# ior7f701503 register map
Registers are 8-bit, access not given, no defined reset value unless marked. A register's access mark holds for its fields unless they carry their own. Addresses are absolute; registers are grouped by the start of their names; [hi:lo] are bit positions; {n}, {i} and the like mark numbered series.

## SFR (part 4 of 4)
0xFFFEEA37 ICCSIH1IREH_1
  [7] CTCSIG0IC ro, [7] CTCSIH1IRE_1 ro, [4] RFCSIG0IC, [4] RFCSIH1IRE_1
0xFFFEEA38 ICCSIG0IR 16-bit
0xFFFEEA38 ICCSIG0IRL
0xFFFEEA38 ICCSIH1IJC_1 16-bit
0xFFFEEA38 ICCSIH1IJCL_1
  [7] MKCSIG0IR, [7] MKCSIH1IJC_1, [6] TBCSIG0IR, [6] TBCSIH1IJC_1, [n] P{n}CSIG0IR (n=0..3), [n] P{n}CSIH1IJC_1 (n=0..3)
0xFFFEEA39 ICCSIG0IRH
0xFFFEEA39 ICCSIH1IJCH_1
  [7] CTCSIG0IR ro, [7] CTCSIH1IJC_1 ro, [4] RFCSIG0IR, [4] RFCSIH1IJC_1
0xFFFEEA3A ICCSIH0IC 16-bit
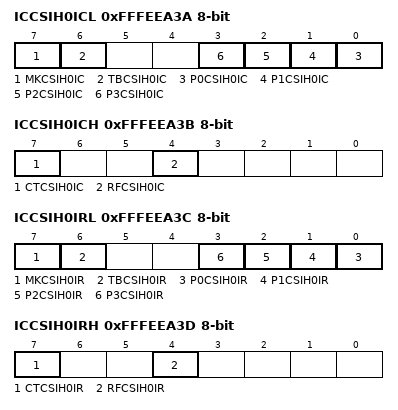
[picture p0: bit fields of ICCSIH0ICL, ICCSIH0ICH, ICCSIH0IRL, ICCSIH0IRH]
0xFFFEEA3A ICCSIH0ICL
  [7] MKCSIH0IC, [6] TBCSIH0IC, [n] P{n}CSIH0IC (n=0..3)
0xFFFEEA3B ICCSIH0ICH
  [7] CTCSIH0IC ro, [4] RFCSIH0IC
0xFFFEEA3C ICCSIH0IR 16-bit
0xFFFEEA3C ICCSIH0IRL
  [7] MKCSIH0IR, [6] TBCSIH0IR, [n] P{n}CSIH0IR (n=0..3)
0xFFFEEA3D ICCSIH0IRH
  [7] CTCSIH0IR ro, [4] RFCSIH0IR
0xFFFEEA3E ICCSIH0IRE 16-bit
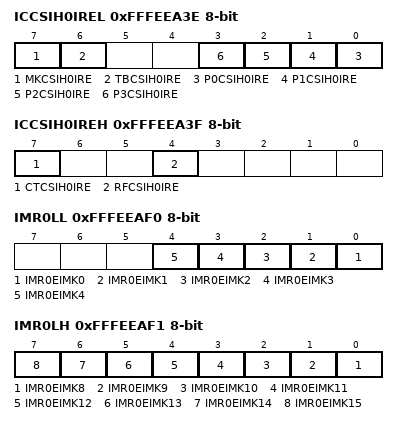
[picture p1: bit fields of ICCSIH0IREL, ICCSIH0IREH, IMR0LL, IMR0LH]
0xFFFEEA3E ICCSIH0IREL
  [7] MKCSIH0IRE, [6] TBCSIH0IRE, [n] P{n}CSIH0IRE (n=0..3)
0xFFFEEA3F ICCSIH0IREH
  [7] CTCSIH0IRE ro, [4] RFCSIH0IRE
0xFFFEEA78 FNC 16-bit ro
0xFFFEEA79 FNCH ro
  [4] FNRF
0xFFFEEA7A FIC 16-bit ro
0xFFFEEA7B FICH ro
  [4] FIRF
0xFFFEEAF0 IMR0 32-bit
0xFFFEEAF0 IMR0L 16-bit
0xFFFEEAF0 IMR0LL
  [n] IMR0EIMK{n} (n=0..4)
0xFFFEEAF1 IMR0LH
  [n-8] IMR0EIMK{n} (n=8..15)
0xFFFEEAF2 IMR0H 16-bit
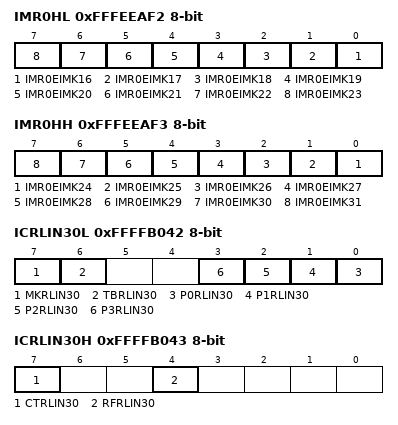
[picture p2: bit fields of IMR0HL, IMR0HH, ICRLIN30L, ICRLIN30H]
0xFFFEEAF2 IMR0HL
  [n-16] IMR0EIMK{n} (n=16..23)
0xFFFEEAF3 IMR0HH
  [n-24] IMR0EIMK{n} (n=24..31)
{0xFFFEEB00+4i} IBDIPIR{i} 32-bit (i=0..3)
0xFFFEEB10 IBDBN0 32-bit
0xFFFEEB20 IBDTAUD0I0 32-bit
0xFFFEEB20 IBDCSIH2IC_1 32-bit
0xFFFEEB24 IBDTAUD0I2 32-bit
0xFFFEEB24 IBDCSIH3IC_1 32-bit
0xFFFEEB28 IBDTAUD0I4 32-bit
0xFFFEEB28 IBDCSIH2IR_1 32-bit
0xFFFEEB2C IBDTAUD0I6 32-bit
0xFFFEEB2C IBDCSIH2IRE_1 32-bit
0xFFFEEB30 IBDTAUD0I8 32-bit
0xFFFEEB30 IBDCSIH2IJC_1 32-bit
0xFFFEEB34 IBDTAUD0I10 32-bit
0xFFFEEB34 IBDCSIH3IR_1 32-bit
0xFFFEEB38 IBDTAUD0I12 32-bit
0xFFFEEB38 IBDCSIH3IRE_1 32-bit
0xFFFEEB3C IBDTAUD0I14 32-bit
0xFFFEEB3C IBDCSIH3IJC_1 32-bit
0xFFFEEB40 IBDTAPA0IPEK0 32-bit
0xFFFEEB40 IBDCSIH1IC_1 32-bit
0xFFFEEB44 IBDTAPA0IVLY0 32-bit
0xFFFEEB44 IBDCSIH1IR_1 32-bit
{0xFFFEEB48+4i} IBDADCA0I{i} 32-bit (i=0..2)
0xFFFEEB50 IBDCSIH0IJC_1 32-bit
0xFFFEEB54 IBDDCUTDI 32-bit
0xFFFEEB58 IBDRCANGERR0 32-bit
0xFFFEEB5C IBDRCANGRECC0 32-bit
0xFFFEEB60 IBDRCAN0ERR 32-bit
0xFFFEEB64 IBDRCAN0REC 32-bit
0xFFFEEB68 IBDRCAN0TRX 32-bit
0xFFFEEB6C IBDCSIG0IC 32-bit
0xFFFEEB6C IBDCSIH1IRE_1 32-bit
0xFFFEEB70 IBDCSIG0IR 32-bit
0xFFFEEB70 IBDCSIH1IJC_1 32-bit
0xFFFEEB74 IBDCSIH0IC 32-bit
0xFFFEEB78 IBDCSIH0IR 32-bit
0xFFFEEB7C IBDCSIH0IRE 32-bit
{0xFFFEEC00+4i} G0MEV{i} 32-bit (i=0..31)
{0xFFFEEC00+4i} G0MEV{i}L 16-bit (i=0..31)
{0xFFFEEC00+4i} G0MEV{i}LL (i=0..31)
{0xFFFEEC01+4i} G0MEV{i}LH (i=0..31)
{0xFFFEEC02+4i} G0MEV{i}H 16-bit (i=0..31)
{0xFFFEEC02+4i} G0MEV{i}HL (i=0..31)
{0xFFFEEC03+4i} G0MEV{i}HH (i=0..31)
0xFFFF8000 DMACTL 32-bit
0xFFFF8020 DMACER 32-bit ro
0xFFFF8030 DM0CMV 32-bit ro
0xFFFF8034 DM1CMV 32-bit ro
0xFFFF803C CMVC 32-bit
0xFFFF8040 DM2CMV 32-bit ro
0xFFFF8044 DM3CMV 32-bit ro
{0xFFFF8100+4i} DM{i:02}CM 32-bit (i=0..7)
{0xFFFF80F8+4i} DM{i}CM 32-bit (i=10..17)
{0xFFFF80F0+4i} DM{i}CM 32-bit (i=20..27)
{0xFFFF80E8+4i} DM{i}CM 32-bit (i=30..37)
{0xFFFF8400+0x40*i} DSA{i} 32-bit (i=0..31)
{0xFFFF8404+0x40*i} DDA{i} 32-bit (i=0..31)
{0xFFFF8408+0x40*i} DTC{i} 32-bit (i=0..31)
{0xFFFF840C+0x40*i} DTCT{i} 32-bit (i=0..31)
{0xFFFF8410+0x40*i} DRSA{i} 32-bit (i=0..31)
{0xFFFF8414+0x40*i} DRDA{i} 32-bit (i=0..31)
{0xFFFF8418+0x40*i} DRTC{i} 32-bit (i=0..31)
{0xFFFF841C+0x40*i} DTCC{i} 32-bit (i=0..31)
{0xFFFF8420+0x40*i} DCEN{i} 32-bit (i=0..31)
{0xFFFF8424+0x40*i} DCST{i} 32-bit ro (i=0..31)
{0xFFFF8428+0x40*i} DCSTS{i} 32-bit (i=0..31)
{0xFFFF842C+0x40*i} DCSTC{i} 32-bit (i=0..31)
{0xFFFF8430+0x40*i} DTFR{i} 32-bit (i=0..31)
{0xFFFF8434+0x40*i} DTFRRQ{i} 32-bit ro (i=0..31)
{0xFFFF8438+0x40*i} DTFRRQC{i} 32-bit (i=0..31)
0xFFFFB040 ICCSIH0IJC 16-bit
0xFFFFB040 ICCSIH0IJCL
  [7] MKADCA0I2_2, [7] MKCSIH0IJC, [6] TBADCA0I2_2, [6] TBCSIH0IJC, [n] P{n}ADCA0I2_2 (n=0..3), [n] P{n}CSIH0IJC (n=0..3)
0xFFFFB040 ICADCA0I2_2 16-bit
0xFFFFB040 ICADCA0I2L_2
0xFFFFB041 ICCSIH0IJCH
  [7] CTADCA0I2_2 ro, [7] CTCSIH0IJC ro, [4] RFADCA0I2_2, [4] RFCSIH0IJC
0xFFFFB041 ICADCA0I2H_2
0xFFFFB042 ICRLIN30 16-bit
0xFFFFB042 ICRLIN30L
  [7] MKRLIN30, [6] TBRLIN30, [n] P{n}RLIN30 (n=0..3)
0xFFFFB043 ICRLIN30H
  [7] CTRLIN30 ro, [4] RFRLIN30
{0xFFFFB044+2i} ICRLIN30UR{i} 16-bit (i=0..2)
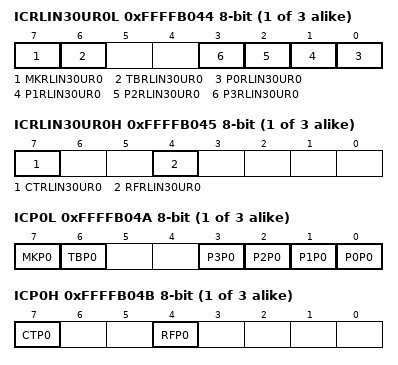
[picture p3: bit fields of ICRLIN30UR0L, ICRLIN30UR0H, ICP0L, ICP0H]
{0xFFFFB044+2i} ICRLIN30UR{i}L (i=0..2)
  [7] MKRLIN30UR{i}, [6] TBRLIN30UR{i}, [n] P{n}RLIN30UR{i} (n=0..3)
{0xFFFFB045+2i} ICRLIN30UR{i}H (i=0..2)
  [7] CTRLIN30UR{i} ro, [4] RFRLIN30UR{i}
{0xFFFFB04A+2i} ICP{i} 16-bit (i=0..2)
{0xFFFFB04A+2i} ICP{i}L (i=0..2)
  [7] MKP{i}, [6] TBP{i}, [n] P{n}P{i} (n=0..3)
{0xFFFFB04B+2i} ICP{i}H (i=0..2)
  [7] CTP{i} ro, [4] RFP{i}
{0xFFFFB050+2i} ICWDTA{i} 16-bit (i=0..2)
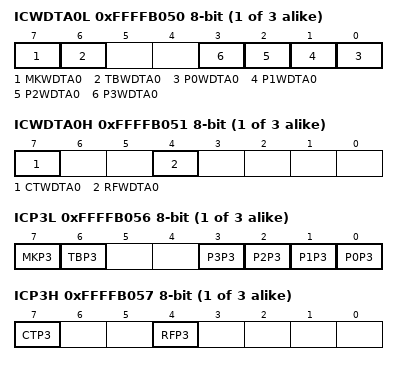
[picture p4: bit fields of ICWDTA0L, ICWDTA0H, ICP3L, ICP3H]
{0xFFFFB050+2i} ICWDTA{i}L (i=0..2)
  [7] MKWDTA{i}, [6] TBWDTA{i}, [n] P{n}WDTA{i} (n=0..3)
{0xFFFFB051+2i} ICWDTA{i}H (i=0..2)
  [7] CTWDTA{i} ro, [4] RFWDTA{i}
{0xFFFFB050+2i} ICP{i} 16-bit (i=3..5)
{0xFFFFB050+2i} ICP{i}L (i=3..5)
  [7] MKP{i}, [6] TBP{i}, [n] P{n}P{i} (n=0..3)
{0xFFFFB051+2i} ICP{i}H (i=3..5)
  [7] CTP{i} ro, [4] RFP{i}
0xFFFFB05C ICP10 16-bit
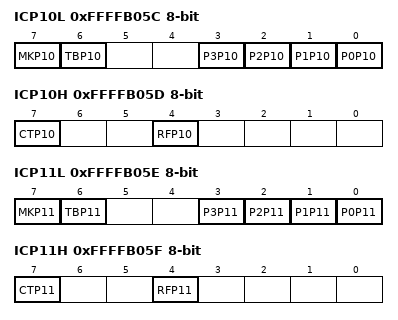
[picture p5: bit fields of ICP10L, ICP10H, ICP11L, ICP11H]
0xFFFFB05C ICP10L
  [7] MKP10, [6] TBP10, [n] P{n}P10 (n=0..3)
0xFFFFB05D ICP10H
  [7] CTP10 ro, [4] RFP10
0xFFFFB05E ICP11 16-bit
0xFFFFB05E ICP11L
  [7] MKP11, [6] TBP11, [n] P{n}P11 (n=0..3)
0xFFFFB05F ICP11H
  [7] CTP11 ro, [4] RFP11
0xFFFFB060 ICTAUD0I1 16-bit
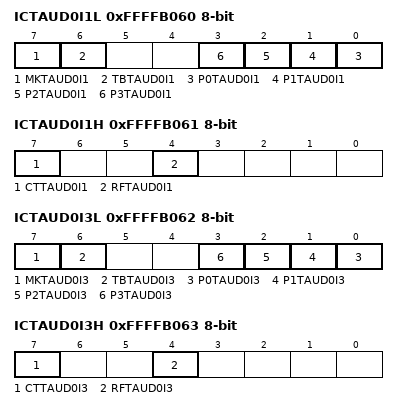
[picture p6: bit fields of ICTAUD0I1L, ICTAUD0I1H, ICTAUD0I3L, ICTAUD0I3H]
0xFFFFB060 ICTAUD0I1L
  [7] MKTAUD0I1, [6] TBTAUD0I1, [n] P{n}TAUD0I1 (n=0..3)
0xFFFFB061 ICTAUD0I1H
  [7] CTTAUD0I1 ro, [4] RFTAUD0I1
0xFFFFB062 ICTAUD0I3 16-bit
0xFFFFB062 ICTAUD0I3L
  [7] MKTAUD0I3, [6] TBTAUD0I3, [n] P{n}TAUD0I3 (n=0..3)
0xFFFFB063 ICTAUD0I3H
  [7] CTTAUD0I3 ro, [4] RFTAUD0I3
0xFFFFB064 ICTAUD0I5 16-bit
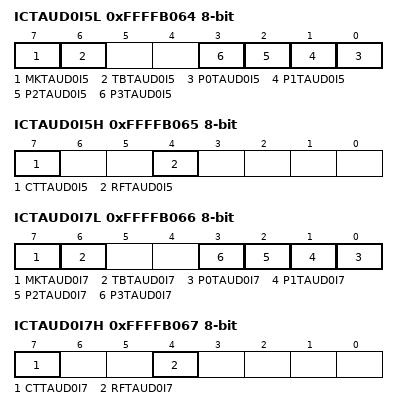
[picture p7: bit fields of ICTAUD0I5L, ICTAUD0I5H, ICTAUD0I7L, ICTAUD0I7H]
0xFFFFB064 ICTAUD0I5L
  [7] MKTAUD0I5, [6] TBTAUD0I5, [n] P{n}TAUD0I5 (n=0..3)
0xFFFFB065 ICTAUD0I5H
  [7] CTTAUD0I5 ro, [4] RFTAUD0I5
0xFFFFB066 ICTAUD0I7 16-bit
0xFFFFB066 ICTAUD0I7L
  [7] MKTAUD0I7, [6] TBTAUD0I7, [n] P{n}TAUD0I7 (n=0..3)
0xFFFFB067 ICTAUD0I7H
  [7] CTTAUD0I7 ro, [4] RFTAUD0I7
0xFFFFB068 ICTAUD0I9 16-bit
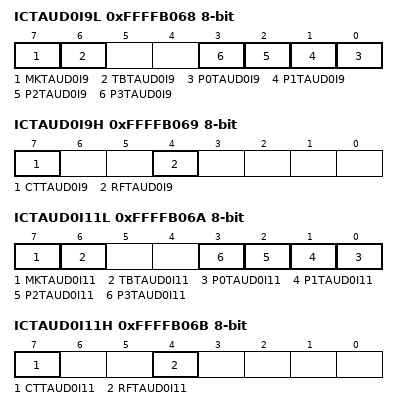
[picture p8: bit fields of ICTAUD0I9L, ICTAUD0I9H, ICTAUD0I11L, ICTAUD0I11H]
0xFFFFB068 ICTAUD0I9L
  [7] MKTAUD0I9, [6] TBTAUD0I9, [n] P{n}TAUD0I9 (n=0..3)
0xFFFFB069 ICTAUD0I9H
  [7] CTTAUD0I9 ro, [4] RFTAUD0I9
0xFFFFB06A ICTAUD0I11 16-bit
0xFFFFB06A ICTAUD0I11L
  [7] MKTAUD0I11, [6] TBTAUD0I11, [n] P{n}TAUD0I11 (n=0..3)
0xFFFFB06B ICTAUD0I11H
  [7] CTTAUD0I11 ro, [4] RFTAUD0I11
0xFFFFB06C ICTAUD0I13 16-bit
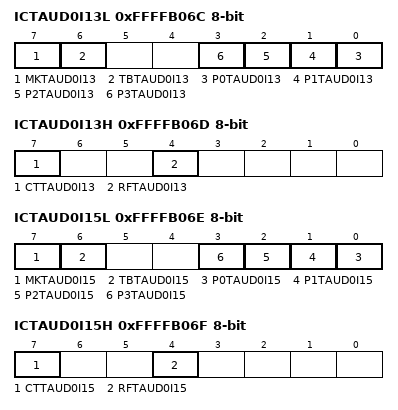
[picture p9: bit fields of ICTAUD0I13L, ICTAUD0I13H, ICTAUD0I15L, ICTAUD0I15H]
0xFFFFB06C ICTAUD0I13L
  [7] MKTAUD0I13, [6] TBTAUD0I13, [n] P{n}TAUD0I13 (n=0..3)
0xFFFFB06D ICTAUD0I13H
  [7] CTTAUD0I13 ro, [4] RFTAUD0I13
0xFFFFB06E ICTAUD0I15 16-bit
0xFFFFB06E ICTAUD0I15L
  [7] MKTAUD0I15, [6] TBTAUD0I15, [n] P{n}TAUD0I15 (n=0..3)
0xFFFFB06F ICTAUD0I15H
  [7] CTTAUD0I15 ro, [4] RFTAUD0I15
0xFFFFB070 ICADCA0ERR 16-bit
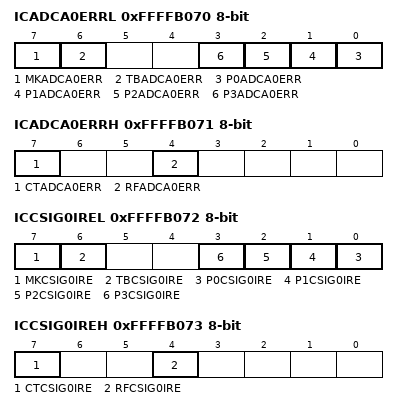
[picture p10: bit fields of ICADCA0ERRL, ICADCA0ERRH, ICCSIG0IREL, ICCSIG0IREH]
0xFFFFB070 ICADCA0ERRL
  [7] MKADCA0ERR, [6] TBADCA0ERR, [n] P{n}ADCA0ERR (n=0..3)
0xFFFFB071 ICADCA0ERRH
  [7] CTADCA0ERR ro, [4] RFADCA0ERR
0xFFFFB072 ICCSIG0IRE 16-bit
0xFFFFB072 ICCSIG0IREL
  [7] MKCSIG0IRE, [6] TBCSIG0IRE, [n] P{n}CSIG0IRE (n=0..3)
0xFFFFB073 ICCSIG0IREH
  [7] CTCSIG0IRE ro, [4] RFCSIG0IRE
0xFFFFB074 ICRLIN20 16-bit
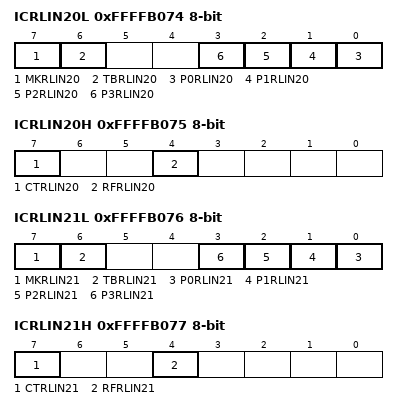
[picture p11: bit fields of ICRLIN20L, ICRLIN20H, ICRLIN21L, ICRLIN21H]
0xFFFFB074 ICRLIN20L
  [7] MKRLIN20, [6] TBRLIN20, [n] P{n}RLIN20 (n=0..3)
0xFFFFB075 ICRLIN20H
  [7] CTRLIN20 ro, [4] RFRLIN20
0xFFFFB076 ICRLIN21 16-bit
0xFFFFB076 ICRLIN21L
  [7] MKRLIN21, [6] TBRLIN21, [n] P{n}RLIN21 (n=0..3)
0xFFFFB077 ICRLIN21H
  [7] CTRLIN21 ro, [4] RFRLIN21
{0xFFFFB078+2i} ICDMA{i} 16-bit (i=0..15)
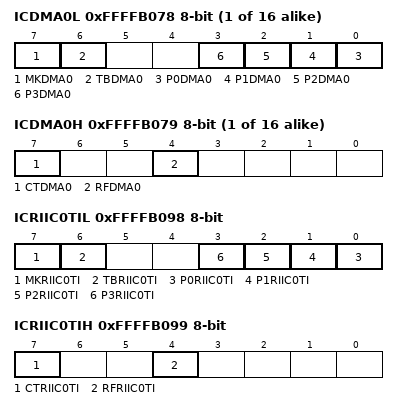
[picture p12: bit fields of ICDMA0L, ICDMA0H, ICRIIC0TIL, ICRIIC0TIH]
{0xFFFFB078+2i} ICDMA{i}L (i=0..15)
  [7] MKDMA{i}, [6] TBDMA{i}, [n] P{n}DMA{i} (n=0..3)
{0xFFFFB079+2i} ICDMA{i}H (i=0..15)
  [7] CTDMA{i} ro, [4] RFDMA{i}
0xFFFFB098 ICRIIC0TI 16-bit
0xFFFFB098 ICRIIC0TIL
  [7] MKRIIC0TI, [6] TBRIIC0TI, [n] P{n}RIIC0TI (n=0..3)
0xFFFFB099 ICRIIC0TIH
  [7] CTRIIC0TI ro, [4] RFRIIC0TI
0xFFFFB09A ICRIIC0TEI 16-bit
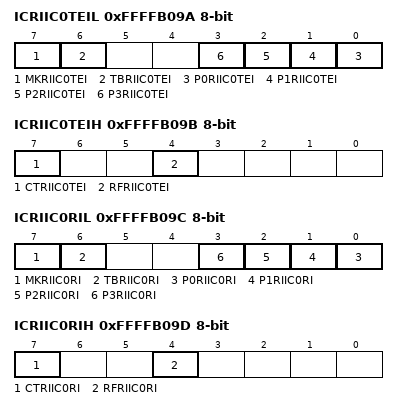
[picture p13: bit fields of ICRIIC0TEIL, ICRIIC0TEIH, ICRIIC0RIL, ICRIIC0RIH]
0xFFFFB09A ICRIIC0TEIL
  [7] MKRIIC0TEI, [6] TBRIIC0TEI, [n] P{n}RIIC0TEI (n=0..3)
0xFFFFB09B ICRIIC0TEIH
  [7] CTRIIC0TEI ro, [4] RFRIIC0TEI
0xFFFFB09C ICRIIC0RI 16-bit
0xFFFFB09C ICRIIC0RIL
  [7] MKRIIC0RI, [6] TBRIIC0RI, [n] P{n}RIIC0RI (n=0..3)
0xFFFFB09D ICRIIC0RIH
  [7] CTRIIC0RI ro, [4] RFRIIC0RI
0xFFFFB09E ICRIIC0EE 16-bit
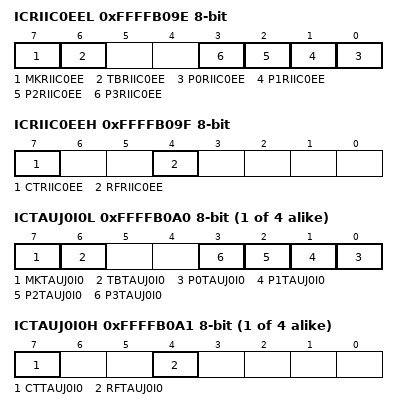
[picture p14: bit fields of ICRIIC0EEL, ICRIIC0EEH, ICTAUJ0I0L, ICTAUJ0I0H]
0xFFFFB09E ICRIIC0EEL
  [7] MKRIIC0EE, [6] TBRIIC0EE, [n] P{n}RIIC0EE (n=0..3)
0xFFFFB09F ICRIIC0EEH
  [7] CTRIIC0EE ro, [4] RFRIIC0EE
{0xFFFFB0A0+2i} ICTAUJ0I{i} 16-bit (i=0..3)
{0xFFFFB0A0+2i} ICTAUJ0I{i}L (i=0..3)
  [7] MKTAUJ0I{i}, [6] TBTAUJ0I{i}, [n] P{n}TAUJ0I{i} (n=0..3)
{0xFFFFB0A1+2i} ICTAUJ0I{i}H (i=0..3)
  [7] CTTAUJ0I{i} ro, [4] RFTAUJ0I{i}
0xFFFFB0A8 ICOSTM0 16-bit
0xFFFFB0A8 ICOSTM0L
  [7] MKOSTM0, [6] TBOSTM0, [n] P{n}OSTM0 (n=0..3)
0xFFFFB0A9 ICOSTM0H
  [7] CTOSTM0 ro, [4] RFOSTM0
0xFFFFB0AA ICENCA0IOV 16-bit
{0xFFFFB0A2+2i} ICPWGA{i} 16-bit (i=4..7)
0xFFFFB0AA ICENCA0IOVL
0xFFFFB0AA ICPWGA4L
  [7] MKENCA0IOV, [7] MKPWGA4, [6] TBENCA0IOV, [6] TBPWGA4, [n] P{n}ENCA0IOV (n=0..3), [n] P{n}PWGA4 (n=0..3)
0xFFFFB0AB ICENCA0IOVH
0xFFFFB0AB ICPWGA4H
  [7] CTENCA0IOV ro, [7] CTPWGA4 ro, [4] RFENCA0IOV, [4] RFPWGA4
0xFFFFB0AC ICENCA0IUD 16-bit
0xFFFFB0AC ICENCA0IUDL
0xFFFFB0AC ICPWGA5L
  [7] MKENCA0IUD, [7] MKPWGA5, [6] TBENCA0IUD, [6] TBPWGA5, [n] P{n}ENCA0IUD (n=0..3), [n] P{n}PWGA5 (n=0..3)
0xFFFFB0AD ICENCA0IUDH
0xFFFFB0AD ICPWGA5H
  [7] CTENCA0IUD ro, [7] CTPWGA5 ro, [4] RFENCA0IUD, [4] RFPWGA5
0xFFFFB0AE ICENCA0I0 16-bit
0xFFFFB0AE ICENCA0I0L
0xFFFFB0AE ICPWGA6L
  [7] MKENCA0I0, [7] MKPWGA6, [6] TBENCA0I0, [6] TBPWGA6, [n] P{n}ENCA0I0 (n=0..3), [n] P{n}PWGA6 (n=0..3)
0xFFFFB0AF ICENCA0I0H
0xFFFFB0AF ICPWGA6H
  [7] CTENCA0I0 ro, [7] CTPWGA6 ro, [4] RFENCA0I0, [4] RFPWGA6
0xFFFFB0B0 ICENCA0I1 16-bit
0xFFFFB0B0 ICENCA0I1L
0xFFFFB0B0 ICPWGA7L
  [7] MKENCA0I1, [7] MKPWGA7, [6] TBENCA0I1, [6] TBPWGA7, [n] P{n}ENCA0I1 (n=0..3), [n] P{n}PWGA7 (n=0..3)
0xFFFFB0B1 ICENCA0I1H
0xFFFFB0B1 ICPWGA7H
  [7] CTENCA0I1 ro, [7] CTPWGA7 ro, [4] RFENCA0I1, [4] RFPWGA7
0xFFFFB0B2 ICENCA0IEC 16-bit
0xFFFFB0B2 ICENCA0IECL
  [7] MKENCA0IEC, [6] TBENCA0IEC, [n] P{n}ENCA0IEC (n=0..3)
0xFFFFB0B3 ICENCA0IECH
  [7] CTENCA0IEC ro, [4] RFENCA0IEC
0xFFFFB0B4 ICKR0 16-bit
0xFFFFB0B4 ICKR0L
  [7] MKKR0, [6] TBKR0, [n] P{n}KR0 (n=0..3)
0xFFFFB0B5 ICKR0H
  [7] CTKR0 ro, [4] RFKR0
0xFFFFB0B6 ICQFULL 16-bit
0xFFFFB0B6 ICQFULLL
  [7] MKQFULL, [6] TBQFULL, [n] P{n}QFULL (n=0..3)
0xFFFFB0B7 ICQFULLH
  [7] CTQFULL ro, [4] RFQFULL
{0xFFFFB0B8+2i} ICPWGA{i} 16-bit (i=0..3)
{0xFFFFB0B8+2i} ICPWGA{i}L (i=0..3)
  [7] MKPWGA{i}, [6] TBPWGA{i}, [n] P{n}PWGA{i} (n=0..3)
{0xFFFFB0B9+2i} ICPWGA{i}H (i=0..3)
  [7] CTPWGA{i} ro, [4] RFPWGA{i}
{0xFFFFB0B0+2i} ICPWGA{i} 16-bit (i=8..15)
{0xFFFFB0B0+2i} ICPWGA{i}L (i=8..15)
  [7] MKPWGA{i}, [6] TBPWGA{i}, [n] P{n}PWGA{i} (n=0..3)
{0xFFFFB0B1+2i} ICPWGA{i}H (i=8..15)
  [7] CTPWGA{i} ro, [4] RFPWGA{i}
0xFFFFB0DC ICFLERR 16-bit
0xFFFFB0DC ICFLERRL
  [7] MKFLERR, [6] TBFLERR, [n] P{n}FLERR (n=0..3)
0xFFFFB0DD ICFLERRH
  [7] CTFLERR ro, [4] RFFLERR
0xFFFFB0DE ICFLENDNM 16-bit
0xFFFFB0DE ICFLENDNML
  [7] MKFLENDNM, [6] TBFLENDNM, [n] P{n}FLENDNM (n=0..3)
0xFFFFB0DF ICFLENDNMH
  [7] CTFLENDNM ro, [4] RFFLENDNM
0xFFFFB0E0 ICCWEND 16-bit
0xFFFFB0E0 ICCWENDL
  [7] MKCWEND, [6] TBCWEND, [n] P{n}CWEND (n=0..3)
0xFFFFB0E1 ICCWENDH
  [7] CTCWEND ro, [4] RFCWEND
0xFFFFB0E2 ICRCAN1ERR 16-bit
0xFFFFB0E2 ICRCAN1ERRL
  [7] MKRCAN1ERR, [6] TBRCAN1ERR, [n] P{n}RCAN1ERR (n=0..3)
0xFFFFB0E3 ICRCAN1ERRH
  [7] CTRCAN1ERR ro, [4] RFRCAN1ERR
0xFFFFB0E4 ICRCAN1REC 16-bit
0xFFFFB0E4 ICRCAN1RECL
  [7] MKRCAN1REC, [6] TBRCAN1REC, [n] P{n}RCAN1REC (n=0..3)
0xFFFFB0E5 ICRCAN1RECH
  [7] CTRCAN1REC ro, [4] RFRCAN1REC
0xFFFFB0E6 ICRCAN1TRX 16-bit
0xFFFFB0E6 ICRCAN1TRXL
  [7] MKRCAN1TRX, [6] TBRCAN1TRX, [n] P{n}RCAN1TRX (n=0..3)
0xFFFFB0E7 ICRCAN1TRXH
  [7] CTRCAN1TRX ro, [4] RFRCAN1TRX
0xFFFFB0E8 ICCSIH1IC 16-bit
0xFFFFB0E8 ICCSIH1ICL
0xFFFFB0E8 ICTAPA0IPEK0_2 16-bit
0xFFFFB0E8 ICTAPA0IPEK0L_2
  [7] MKCSIH1IC, [7] MKTAPA0IPEK0_2, [6] TBCSIH1IC, [6] TBTAPA0IPEK0_2, [n] P{n}CSIH1IC (n=0..3), [n] P{n}TAPA0IPEK0_2 (n=0..3)
0xFFFFB0E9 ICCSIH1ICH
0xFFFFB0E9 ICTAPA0IPEK0H_2
  [7] CTCSIH1IC ro, [7] CTTAPA0IPEK0_2 ro, [4] RFCSIH1IC, [4] RFTAPA0IPEK0_2
0xFFFFB0EA ICCSIH1IR 16-bit
0xFFFFB0EA ICCSIH1IRL
0xFFFFB0EA ICTAPA0IVLY0_2 16-bit
0xFFFFB0EA ICTAPA0IVLY0L_2
  [7] MKCSIH1IR, [7] MKTAPA0IVLY0_2, [6] TBCSIH1IR, [6] TBTAPA0IVLY0_2, [n] P{n}CSIH1IR (n=0..3), [n] P{n}TAPA0IVLY0_2 (n=0..3)
0xFFFFB0EB ICCSIH1IRH
0xFFFFB0EB ICTAPA0IVLY0H_2
  [7] CTCSIH1IR ro, [7] CTTAPA0IVLY0_2 ro, [4] RFCSIH1IR, [4] RFTAPA0IVLY0_2
0xFFFFB0EC ICCSIH1IRE 16-bit
0xFFFFB0EC ICCSIH1IREL
  [7] MKCSIG0IC_2, [7] MKCSIH1IRE, [6] TBCSIG0IC_2, [6] TBCSIH1IRE, [n] P{n}CSIG0IC_2 (n=0..3), [n] P{n}CSIH1IRE (n=0..3)
0xFFFFB0EC ICCSIG0IC_2 16-bit
0xFFFFB0EC ICCSIG0ICL_2
0xFFFFB0ED ICCSIH1IREH
  [7] CTCSIG0IC_2 ro, [7] CTCSIH1IRE ro, [4] RFCSIG0IC_2, [4] RFCSIH1IRE
0xFFFFB0ED ICCSIG0ICH_2
0xFFFFB0EE ICCSIH1IJC 16-bit
0xFFFFB0EE ICCSIH1IJCL
  [7] MKCSIG0IR_2, [7] MKCSIH1IJC, [6] TBCSIG0IR_2, [6] TBCSIH1IJC, [n] P{n}CSIG0IR_2 (n=0..3), [n] P{n}CSIH1IJC (n=0..3)
0xFFFFB0EE ICCSIG0IR_2 16-bit
0xFFFFB0EE ICCSIG0IRL_2
0xFFFFB0EF ICCSIH1IJCH
  [7] CTCSIG0IR_2 ro, [7] CTCSIH1IJC ro, [4] RFCSIG0IR_2, [4] RFCSIH1IJC
0xFFFFB0EF ICCSIG0IRH_2
0xFFFFB0F0 ICRLIN31 16-bit
0xFFFFB0F0 ICRLIN31L
  [7] MKRLIN31, [6] TBRLIN31, [n] P{n}RLIN31 (n=0..3)
0xFFFFB0F1 ICRLIN31H
  [7] CTRLIN31 ro, [4] RFRLIN31
{0xFFFFB0F2+2i} ICRLIN31UR{i} 16-bit (i=0..2)
{0xFFFFB0F2+2i} ICRLIN31UR{i}L (i=0..2)
  [7] MKRLIN31UR{i}, [6] TBRLIN31UR{i}, [n] P{n}RLIN31UR{i} (n=0..3)
{0xFFFFB0F3+2i} ICRLIN31UR{i}H (i=0..2)
  [7] CTRLIN31UR{i} ro, [4] RFRLIN31UR{i}
{0xFFFFB0D0+2i} ICPWGA{i} 16-bit (i=20..23)
{0xFFFFB0D0+2i} ICPWGA{i}L (i=20..23)
  [7] MKPWGA{i}, [6] TBPWGA{i}, [n] P{n}PWGA{i} (n=0..3)
{0xFFFFB0D1+2i} ICPWGA{i}H (i=20..23)
  [7] CTPWGA{i} ro, [4] RFPWGA{i}
{0xFFFFB0F4+2i} ICP{i} 16-bit (i=6..8)
{0xFFFFB0F4+2i} ICP{i}L (i=6..8)
  [7] MKP{i}, [6] TBP{i}, [n] P{n}P{i} (n=0..3)
{0xFFFFB0F5+2i} ICP{i}H (i=6..8)
  [7] CTP{i} ro, [4] RFP{i}
0xFFFFB106 ICP12 16-bit
0xFFFFB106 ICP12L
  [7] MKP12, [6] TBP12, [n] P{n}P12 (n=0..3)
0xFFFFB107 ICP12H
  [7] CTP12 ro, [4] RFP12
0xFFFFB108 ICCSIH2IC 16-bit
0xFFFFB108 ICCSIH2ICL
0xFFFFB108 ICTAUD0I0_2 16-bit
0xFFFFB108 ICTAUD0I0L_2
  [7] MKCSIH2IC, [7] MKTAUD0I0_2, [6] TBCSIH2IC, [6] TBTAUD0I0_2, [n] P{n}CSIH2IC (n=0..3), [n] P{n}TAUD0I0_2 (n=0..3)
0xFFFFB109 ICCSIH2ICH
0xFFFFB109 ICTAUD0I0H_2
  [7] CTCSIH2IC ro, [7] CTTAUD0I0_2 ro, [4] RFCSIH2IC, [4] RFTAUD0I0_2
0xFFFFB10A ICCSIH2IR 16-bit
0xFFFFB10A ICCSIH2IRL
0xFFFFB10A ICTAUD0I4_2 16-bit
0xFFFFB10A ICTAUD0I4L_2
  [7] MKCSIH2IR, [7] MKTAUD0I4_2, [6] TBCSIH2IR, [6] TBTAUD0I4_2, [n] P{n}CSIH2IR (n=0..3), [n] P{n}TAUD0I4_2 (n=0..3)
0xFFFFB10B ICCSIH2IRH
0xFFFFB10B ICTAUD0I4H_2
  [7] CTCSIH2IR ro, [7] CTTAUD0I4_2 ro, [4] RFCSIH2IR, [4] RFTAUD0I4_2
0xFFFFB10C ICCSIH2IRE 16-bit
0xFFFFB10C ICCSIH2IREL
0xFFFFB10C ICTAUD0I6_2 16-bit
0xFFFFB10C ICTAUD0I6L_2
  [7] MKCSIH2IRE, [7] MKTAUD0I6_2, [6] TBCSIH2IRE, [6] TBTAUD0I6_2, [n] P{n}CSIH2IRE (n=0..3), [n] P{n}TAUD0I6_2 (n=0..3)
0xFFFFB10D ICCSIH2IREH
0xFFFFB10D ICTAUD0I6H_2
  [7] CTCSIH2IRE ro, [7] CTTAUD0I6_2 ro, [4] RFCSIH2IRE, [4] RFTAUD0I6_2
0xFFFFB10E ICCSIH2IJC 16-bit
0xFFFFB10E ICCSIH2IJCL
0xFFFFB10E ICTAUD0I8_2 16-bit
0xFFFFB10E ICTAUD0I8L_2
  [7] MKCSIH2IJC, [7] MKTAUD0I8_2, [6] TBCSIH2IJC, [6] TBTAUD0I8_2, [n] P{n}CSIH2IJC (n=0..3), [n] P{n}TAUD0I8_2 (n=0..3)
0xFFFFB10F ICCSIH2IJCH
0xFFFFB10F ICTAUD0I8H_2
  [7] CTCSIH2IJC ro, [7] CTTAUD0I8_2 ro, [4] RFCSIH2IJC, [4] RFTAUD0I8_2
{0xFFFFB11C+2i} ICTAUB0I{i} 16-bit (i=0..15)
{0xFFFFB11C+2i} ICTAUB0I{i}L (i=0..2)
  [7] MKTAUB0I{i}, [6] TBTAUB0I{i}, [n] P{n}TAUB0I{i} (n=0..3)
{0xFFFFB11D+2i} ICTAUB0I{i}H (i=0..2)
  [7] CTTAUB0I{i} ro, [4] RFTAUB0I{i}
{0xFFFFB0E2+4i} ICPWGA{i} 16-bit (i=16..19)
{0xFFFFB0E2+4i} ICPWGA{i}L (i=16..19)
0xFFFFB122 ICTAUB0I3L
  [7] MKPWGA16, [7] MKTAUB0I3, [6] TBPWGA16, [6] TBTAUB0I3, [n] P{n}PWGA16 (n=0..3), [n] P{n}TAUB0I3 (n=0..3)
{0xFFFFB0E3+4i} ICPWGA{i}H (i=16..19)
0xFFFFB123 ICTAUB0I3H
  [7] CTPWGA16 ro, [7] CTTAUB0I3 ro, [4] RFPWGA16, [4] RFTAUB0I3
0xFFFFB124 ICTAUB0I4L
  [7] MKTAUB0I4, [6] TBTAUB0I4, [n] P{n}TAUB0I4 (n=0..3)
0xFFFFB125 ICTAUB0I4H
  [7] CTTAUB0I4 ro, [4] RFTAUB0I4
0xFFFFB126 ICTAUB0I5L
  [7] MKPWGA17, [7] MKTAUB0I5, [6] TBPWGA17, [6] TBTAUB0I5, [n] P{n}PWGA17 (n=0..3), [n] P{n}TAUB0I5 (n=0..3)
0xFFFFB127 ICTAUB0I5H
  [7] CTPWGA17 ro, [7] CTTAUB0I5 ro, [4] RFPWGA17, [4] RFTAUB0I5
0xFFFFB128 ICTAUB0I6L
  [7] MKTAUB0I6, [6] TBTAUB0I6, [n] P{n}TAUB0I6 (n=0..3)
0xFFFFB129 ICTAUB0I6H
  [7] CTTAUB0I6 ro, [4] RFTAUB0I6
0xFFFFB12A ICTAUB0I7L
  [7] MKPWGA18, [7] MKTAUB0I7, [6] TBPWGA18, [6] TBTAUB0I7, [n] P{n}PWGA18 (n=0..3), [n] P{n}TAUB0I7 (n=0..3)
0xFFFFB12B ICTAUB0I7H
  [7] CTPWGA18 ro, [7] CTTAUB0I7 ro, [4] RFPWGA18, [4] RFTAUB0I7
0xFFFFB12C ICTAUB0I8L
  [7] MKTAUB0I8, [6] TBTAUB0I8, [n] P{n}TAUB0I8 (n=0..3)
0xFFFFB12D ICTAUB0I8H
  [7] CTTAUB0I8 ro, [4] RFTAUB0I8
0xFFFFB12E ICTAUB0I9L
  [7] MKPWGA19, [7] MKTAUB0I9, [6] TBPWGA19, [6] TBTAUB0I9, [n] P{n}PWGA19 (n=0..3), [n] P{n}TAUB0I9 (n=0..3)
0xFFFFB12F ICTAUB0I9H
  [7] CTPWGA19 ro, [7] CTTAUB0I9 ro, [4] RFPWGA19, [4] RFTAUB0I9
0xFFFFB130 ICTAUB0I10L
  [7] MKTAUB0I10, [6] TBTAUB0I10, [n] P{n}TAUB0I10 (n=0..3)
0xFFFFB131 ICTAUB0I10H
  [7] CTTAUB0I10 ro, [4] RFTAUB0I10
0xFFFFB132 ICPWGA26 16-bit
0xFFFFB132 ICPWGA26L
0xFFFFB132 ICTAUB0I11L
  [7] MKPWGA26, [7] MKTAUB0I11, [6] TBPWGA26, [6] TBTAUB0I11, [n] P{n}PWGA26 (n=0..3), [n] P{n}TAUB0I11 (n=0..3)
0xFFFFB133 ICPWGA26H
0xFFFFB133 ICTAUB0I11H
  [7] CTPWGA26 ro, [7] CTTAUB0I11 ro, [4] RFPWGA26, [4] RFTAUB0I11
0xFFFFB134 ICTAUB0I12L
  [7] MKTAUB0I12, [6] TBTAUB0I12, [n] P{n}TAUB0I12 (n=0..3)
0xFFFFB135 ICTAUB0I12H
  [7] CTTAUB0I12 ro, [4] RFTAUB0I12
0xFFFFB136 ICPWGA30 16-bit
0xFFFFB136 ICPWGA30L
0xFFFFB136 ICTAUB0I13L
  [7] MKPWGA30, [7] MKTAUB0I13, [6] TBPWGA30, [6] TBTAUB0I13, [n] P{n}PWGA30 (n=0..3), [n] P{n}TAUB0I13 (n=0..3)
0xFFFFB137 ICPWGA30H
0xFFFFB137 ICTAUB0I13H
  [7] CTPWGA30 ro, [7] CTTAUB0I13 ro, [4] RFPWGA30, [4] RFTAUB0I13
0xFFFFB138 ICTAUB0I14L
  [7] MKTAUB0I14, [6] TBTAUB0I14, [n] P{n}TAUB0I14 (n=0..3)
0xFFFFB139 ICTAUB0I14H
  [7] CTTAUB0I14 ro, [4] RFTAUB0I14
0xFFFFB13A ICPWGA31 16-bit
0xFFFFB13A ICPWGA31L
0xFFFFB13A ICTAUB0I15L
  [7] MKPWGA31, [7] MKTAUB0I15, [6] TBPWGA31, [6] TBTAUB0I15, [n] P{n}PWGA31 (n=0..3), [n] P{n}TAUB0I15 (n=0..3)
0xFFFFB13B ICPWGA31H
0xFFFFB13B ICTAUB0I15H
  [7] CTPWGA31 ro, [7] CTTAUB0I15 ro, [4] RFPWGA31, [4] RFTAUB0I15
0xFFFFB13C ICCSIH3IC 16-bit
0xFFFFB13C ICCSIH3ICL
0xFFFFB13C ICTAUD0I2_2 16-bit
0xFFFFB13C ICTAUD0I2L_2
  [7] MKCSIH3IC, [7] MKTAUD0I2_2, [6] TBCSIH3IC, [6] TBTAUD0I2_2, [n] P{n}CSIH3IC (n=0..3), [n] P{n}TAUD0I2_2 (n=0..3)
0xFFFFB13D ICCSIH3ICH
0xFFFFB13D ICTAUD0I2H_2
  [7] CTCSIH3IC ro, [7] CTTAUD0I2_2 ro, [4] RFCSIH3IC, [4] RFTAUD0I2_2
0xFFFFB13E ICCSIH3IR 16-bit
0xFFFFB13E ICCSIH3IRL
0xFFFFB13E ICTAUD0I10_2 16-bit
0xFFFFB13E ICTAUD0I10L_2
  [7] MKCSIH3IR, [7] MKTAUD0I10_2, [6] TBCSIH3IR, [6] TBTAUD0I10_2, [n] P{n}CSIH3IR (n=0..3), [n] P{n}TAUD0I10_2 (n=0..3)
0xFFFFB13F ICCSIH3IRH
0xFFFFB13F ICTAUD0I10H_2
  [7] CTCSIH3IR ro, [7] CTTAUD0I10_2 ro, [4] RFCSIH3IR, [4] RFTAUD0I10_2
0xFFFFB140 ICCSIH3IRE 16-bit
0xFFFFB140 ICCSIH3IREL
0xFFFFB140 ICTAUD0I12_2 16-bit
0xFFFFB140 ICTAUD0I12L_2
  [7] MKCSIH3IRE, [7] MKTAUD0I12_2, [6] TBCSIH3IRE, [6] TBTAUD0I12_2, [n] P{n}CSIH3IRE (n=0..3), [n] P{n}TAUD0I12_2 (n=0..3)
0xFFFFB141 ICCSIH3IREH
0xFFFFB141 ICTAUD0I12H_2
  [7] CTCSIH3IRE ro, [7] CTTAUD0I12_2 ro, [4] RFCSIH3IRE, [4] RFTAUD0I12_2
0xFFFFB142 ICCSIH3IJC 16-bit
0xFFFFB142 ICCSIH3IJCL
0xFFFFB142 ICTAUD0I14_2 16-bit
0xFFFFB142 ICTAUD0I14L_2
  [7] MKCSIH3IJC, [7] MKTAUD0I14_2, [6] TBCSIH3IJC, [6] TBTAUD0I14_2, [n] P{n}CSIH3IJC (n=0..3), [n] P{n}TAUD0I14_2 (n=0..3)
0xFFFFB143 ICCSIH3IJCH
0xFFFFB143 ICTAUD0I14H_2
  [7] CTCSIH3IJC ro, [7] CTTAUD0I14_2 ro, [4] RFCSIH3IJC, [4] RFTAUD0I14_2
0xFFFFB144 ICRLIN22 16-bit
0xFFFFB144 ICRLIN22L
  [7] MKRLIN22, [6] TBRLIN22, [n] P{n}RLIN22 (n=0..3)
0xFFFFB145 ICRLIN22H
  [7] CTRLIN22 ro, [4] RFRLIN22
0xFFFFB146 ICRLIN23 16-bit
0xFFFFB146 ICRLIN23L
  [7] MKRLIN23, [6] TBRLIN23, [n] P{n}RLIN23 (n=0..3)
0xFFFFB147 ICRLIN23H
  [7] CTRLIN23 ro, [4] RFRLIN23
0xFFFFB148 ICRLIN32 16-bit
0xFFFFB148 ICRLIN32L
  [7] MKRLIN32, [6] TBRLIN32, [n] P{n}RLIN32 (n=0..3)
0xFFFFB149 ICRLIN32H
  [7] CTRLIN32 ro, [4] RFRLIN32
{0xFFFFB14A+2i} ICRLIN32UR{i} 16-bit (i=0..2)
{0xFFFFB14A+2i} ICRLIN32UR{i}L (i=0..2)
  [7] MKRLIN32UR{i}, [6] TBRLIN32UR{i}, [n] P{n}RLIN32UR{i} (n=0..3)
{0xFFFFB14B+2i} ICRLIN32UR{i}H (i=0..2)
  [7] CTRLIN32UR{i} ro, [4] RFRLIN32UR{i}
{0xFFFFB150+2i} ICTAUJ1I{i} 16-bit (i=0..3)
{0xFFFFB150+2i} ICTAUJ1I{i}L (i=0..3)
  [7] MKTAUJ1I{i}, [6] TBTAUJ1I{i}, [n] P{n}TAUJ1I{i} (n=0..3)
{0xFFFFB151+2i} ICTAUJ1I{i}H (i=0..3)
  [7] CTTAUJ1I{i} ro, [4] RFTAUJ1I{i}
0xFFFFB15A ICFLXA0FDA 16-bit
0xFFFFB15A ICFLXA0FDAL
  [7] MKFLXA0FDA, [6] TBFLXA0FDA, [n] P{n}FLXA0FDA (n=0..3)
0xFFFFB15B ICFLXA0FDAH
  [7] CTFLXA0FDA ro, [4] RFFLXA0FDA
0xFFFFB15C ICFLXA0FW 16-bit
0xFFFFB15C ICFLXA0FWL
  [7] MKFLXA0FW, [6] TBFLXA0FW, [n] P{n}FLXA0FW (n=0..3)
0xFFFFB15D ICFLXA0FWH
  [7] CTFLXA0FW ro, [4] RFFLXA0FW
0xFFFFB15E ICFLXA0IQE 16-bit
0xFFFFB15E ICFLXA0IQEL
  [7] MKFLXA0IQE, [6] TBFLXA0IQE, [n] P{n}FLXA0IQE (n=0..3)
0xFFFFB15F ICFLXA0IQEH
  [7] CTFLXA0IQE ro, [4] RFFLXA0IQE
0xFFFFB160 ICFLXA0IQF 16-bit
0xFFFFB160 ICFLXA0IQFL
  [7] MKFLXA0IQF, [6] TBFLXA0IQF, [n] P{n}FLXA0IQF (n=0..3)
0xFFFFB161 ICFLXA0IQFH
  [7] CTFLXA0IQF ro, [4] RFFLXA0IQF
0xFFFFB162 ICFLXA0OT 16-bit
0xFFFFB162 ICFLXA0OTL
  [7] MKFLXA0OT, [6] TBFLXA0OT, [n] P{n}FLXA0OT (n=0..3)
0xFFFFB163 ICFLXA0OTH
  [7] CTFLXA0OT ro, [4] RFFLXA0OT
0xFFFFB164 ICFLXA0OW 16-bit
0xFFFFB164 ICFLXA0OWL
  [7] MKFLXA0OW, [6] TBFLXA0OW, [n] P{n}FLXA0OW (n=0..3)
0xFFFFB165 ICFLXA0OWH
  [7] CTFLXA0OW ro, [4] RFFLXA0OW
0xFFFFB166 ICFLXA0LINE0 16-bit
0xFFFFB166 ICFLXA0LINE0L
  [7] MKFLXA0LINE0, [6] TBFLXA0LINE0, [n] P{n}FLXA0LINE0 (n=0..3)
0xFFFFB167 ICFLXA0LINE0H
  [7] CTFLXA0LINE0 ro, [4] RFFLXA0LINE0
0xFFFFB168 ICFLXA0LINE1 16-bit
0xFFFFB168 ICFLXA0LINE1L
  [7] MKFLXA0LINE1, [6] TBFLXA0LINE1, [n] P{n}FLXA0LINE1 (n=0..3)
0xFFFFB169 ICFLXA0LINE1H
  [7] CTFLXA0LINE1 ro, [4] RFFLXA0LINE1
{0xFFFFB16A+2i} ICFLXA0TIM{i} 16-bit (i=0..2)
{0xFFFFB16A+2i} ICFLXA0TIM{i}L (i=0..2)
  [7] MKFLXA0TIM{i}, [6] TBFLXA0TIM{i}, [n] P{n}FLXA0TIM{i} (n=0..3)
{0xFFFFB16B+2i} ICFLXA0TIM{i}H (i=0..2)
  [7] CTFLXA0TIM{i} ro, [4] RFFLXA0TIM{i}
0xFFFFB170 ICPWGA24 16-bit
0xFFFFB170 ICPWGA24L
  [7] MKPWGA24, [6] TBPWGA24, [n] P{n}PWGA24 (n=0..3)
0xFFFFB171 ICPWGA24H
  [7] CTPWGA24 ro, [4] RFPWGA24
0xFFFFB172 ICPWGA25 16-bit
0xFFFFB172 ICPWGA25L
  [7] MKPWGA25, [6] TBPWGA25, [n] P{n}PWGA25 (n=0..3)
0xFFFFB173 ICPWGA25H
  [7] CTPWGA25 ro, [4] RFPWGA25
{0xFFFFB13E+2i} ICPWGA{i} 16-bit (i=27..29)
{0xFFFFB13E+2i} ICPWGA{i}L (i=27..29)
  [7] MKPWGA{i}, [6] TBPWGA{i}, [n] P{n}PWGA{i} (n=0..3)
{0xFFFFB13F+2i} ICPWGA{i}H (i=27..29)
  [7] CTPWGA{i} ro, [4] RFPWGA{i}
{0xFFFFB13A+2i} ICPWGA{i} 16-bit (i=32..47)
{0xFFFFB13A+2i} ICPWGA{i}L (i=32..47)
  [7] MKPWGA{i}, [6] TBPWGA{i}, [n] P{n}PWGA{i} (n=0..3)
{0xFFFFB13B+2i} ICPWGA{i}H (i=32..47)
  [7] CTPWGA{i} ro, [4] RFPWGA{i}
0xFFFFB19A ICP9 16-bit
0xFFFFB19A ICP9L
  [7] MKP9, [6] TBP9, [n] P{n}P9 (n=0..3)
0xFFFFB19B ICP9H
  [7] CTP9 ro, [4] RFP9
{0xFFFFB182+2i} ICP{i} 16-bit (i=13..15)
{0xFFFFB182+2i} ICP{i}L (i=13..15)
  [7] MKP{i}, [6] TBP{i}, [n] P{n}P{i} (n=0..3)
{0xFFFFB183+2i} ICP{i}H (i=13..15)
  [7] CTP{i} ro, [4] RFP{i}
0xFFFFB1A2 ICRTCA01S 16-bit
0xFFFFB1A2 ICRTCA01SL
  [7] MKRTCA01S, [6] TBRTCA01S, [n] P{n}RTCA01S (n=0..3)
0xFFFFB1A3 ICRTCA01SH
  [7] CTRTCA01S ro, [4] RFRTCA01S
0xFFFFB1A4 ICRTCA0AL 16-bit
0xFFFFB1A4 ICRTCA0ALL
  [7] MKRTCA0AL, [6] TBRTCA0AL, [n] P{n}RTCA0AL (n=0..3)
0xFFFFB1A5 ICRTCA0ALH
  [7] CTRTCA0AL ro, [4] RFRTCA0AL
0xFFFFB1A6 ICRTCA0R 16-bit
0xFFFFB1A6 ICRTCA0RL
  [7] MKRTCA0R, [6] TBRTCA0R, [n] P{n}RTCA0R (n=0..3)
0xFFFFB1A7 ICRTCA0RH
  [7] CTRTCA0R ro, [4] RFRTCA0R
0xFFFFB1A8 ICADCA1ERR 16-bit
0xFFFFB1A8 ICADCA1ERRL
  [7] MKADCA1ERR, [6] TBADCA1ERR, [n] P{n}ADCA1ERR (n=0..3)
0xFFFFB1A9 ICADCA1ERRH
  [7] CTADCA1ERR ro, [4] RFADCA1ERR
{0xFFFFB1AA+2i} ICADCA1I{i} 16-bit (i=0..2)
{0xFFFFB1AA+2i} ICADCA1I{i}L (i=0..2)
  [7] MKADCA1I{i}, [6] TBADCA1I{i}, [n] P{n}ADCA1I{i} (n=0..3)
{0xFFFFB1AB+2i} ICADCA1I{i}H (i=0..2)
  [7] CTADCA1I{i} ro, [4] RFADCA1I{i}
0xFFFFB1B2 ICRCAN2ERR 16-bit
0xFFFFB1B2 ICRCAN2ERRL
  [7] MKRCAN2ERR, [6] TBRCAN2ERR, [n] P{n}RCAN2ERR (n=0..3)
0xFFFFB1B3 ICRCAN2ERRH
  [7] CTRCAN2ERR ro, [4] RFRCAN2ERR
0xFFFFB1B4 ICRCAN2REC 16-bit
0xFFFFB1B4 ICRCAN2RECL
  [7] MKRCAN2REC, [6] TBRCAN2REC, [n] P{n}RCAN2REC (n=0..3)
0xFFFFB1B5 ICRCAN2RECH
  [7] CTRCAN2REC ro, [4] RFRCAN2REC
0xFFFFB1B6 ICRCAN2TRX 16-bit
0xFFFFB1B6 ICRCAN2TRXL
  [7] MKRCAN2TRX, [6] TBRCAN2TRX, [n] P{n}RCAN2TRX (n=0..3)
0xFFFFB1B7 ICRCAN2TRXH
  [7] CTRCAN2TRX ro, [4] RFRCAN2TRX
0xFFFFB1B8 ICRCAN3ERR 16-bit
0xFFFFB1B8 ICRCAN3ERRL
  [7] MKRCAN3ERR, [6] TBRCAN3ERR, [n] P{n}RCAN3ERR (n=0..3)
0xFFFFB1B9 ICRCAN3ERRH
  [7] CTRCAN3ERR ro, [4] RFRCAN3ERR
0xFFFFB1BA ICRCAN3REC 16-bit
0xFFFFB1BA ICRCAN3RECL
  [7] MKRCAN3REC, [6] TBRCAN3REC, [n] P{n}RCAN3REC (n=0..3)
0xFFFFB1BB ICRCAN3RECH
  [7] CTRCAN3REC ro, [4] RFRCAN3REC
0xFFFFB1BC ICRCAN3TRX 16-bit
0xFFFFB1BC ICRCAN3TRXL
  [7] MKRCAN3TRX, [6] TBRCAN3TRX, [n] P{n}RCAN3TRX (n=0..3)
0xFFFFB1BD ICRCAN3TRXH
  [7] CTRCAN3TRX ro, [4] RFRCAN3TRX
0xFFFFB1BE ICCSIG1IC 16-bit
0xFFFFB1BE ICCSIG1ICL
  [7] MKCSIG1IC, [6] TBCSIG1IC, [n] P{n}CSIG1IC (n=0..3)
0xFFFFB1BF ICCSIG1ICH
  [7] CTCSIG1IC ro, [4] RFCSIG1IC
0xFFFFB1C0 ICCSIG1IR 16-bit
0xFFFFB1C0 ICCSIG1IRL
  [7] MKCSIG1IR, [6] TBCSIG1IR, [n] P{n}CSIG1IR (n=0..3)
0xFFFFB1C1 ICCSIG1IRH
  [7] CTCSIG1IR ro, [4] RFCSIG1IR
0xFFFFB1C2 ICCSIG1IRE 16-bit
0xFFFFB1C2 ICCSIG1IREL
  [7] MKCSIG1IRE, [6] TBCSIG1IRE, [n] P{n}CSIG1IRE (n=0..3)
0xFFFFB1C3 ICCSIG1IREH
  [7] CTCSIG1IRE ro, [4] RFCSIG1IRE
0xFFFFB1C4 ICRLIN24 16-bit
0xFFFFB1C4 ICRLIN24L
  [7] MKRLIN24, [6] TBRLIN24, [n] P{n}RLIN24 (n=0..3)
0xFFFFB1C5 ICRLIN24H
  [7] CTRLIN24 ro, [4] RFRLIN24
0xFFFFB1C6 ICRLIN25 16-bit
0xFFFFB1C6 ICRLIN25L
  [7] MKRLIN25, [6] TBRLIN25, [n] P{n}RLIN25 (n=0..3)
0xFFFFB1C7 ICRLIN25H
  [7] CTRLIN25 ro, [4] RFRLIN25
{0xFFFFB0C0+8i} ICRLIN{i} 16-bit (i=33..35)
{0xFFFFB0C0+8i} ICRLIN{i}L (i=33..35)
  [7] MKRLIN{i}, [6] TBRLIN{i}, [n] P{n}RLIN{i} (n=0..3)
{0xFFFFB0C1+8i} ICRLIN{i}H (i=33..35)
  [7] CTRLIN{i} ro, [4] RFRLIN{i}
{0xFFFFB1CA+2i} ICRLIN33UR{i} 16-bit (i=0..2)
{0xFFFFB1CA+2i} ICRLIN33UR{i}L (i=0..2)
  [7] MKRLIN33UR{i}, [6] TBRLIN33UR{i}, [n] P{n}RLIN33UR{i} (n=0..3)
{0xFFFFB1CB+2i} ICRLIN33UR{i}H (i=0..2)
  [7] CTRLIN33UR{i} ro, [4] RFRLIN33UR{i}
{0xFFFFB1D2+2i} ICRLIN34UR{i} 16-bit (i=0..2)
{0xFFFFB1D2+2i} ICRLIN34UR{i}L (i=0..2)
  [7] MKRLIN34UR{i}, [6] TBRLIN34UR{i}, [n] P{n}RLIN34UR{i} (n=0..3)
{0xFFFFB1D3+2i} ICRLIN34UR{i}H (i=0..2)
  [7] CTRLIN34UR{i} ro, [4] RFRLIN34UR{i}
{0xFFFFB1DA+2i} ICRLIN35UR{i} 16-bit (i=0..2)
{0xFFFFB1DA+2i} ICRLIN35UR{i}L (i=0..2)
  [7] MKRLIN35UR{i}, [6] TBRLIN35UR{i}, [n] P{n}RLIN35UR{i} (n=0..3)
{0xFFFFB1DB+2i} ICRLIN35UR{i}H (i=0..2)
  [7] CTRLIN35UR{i} ro, [4] RFRLIN35UR{i}
{0xFFFFB180+2i} ICPWGA{i} 16-bit (i=48..63)
{0xFFFFB180+2i} ICPWGA{i}L (i=48..63)
  [7] MKPWGA{i}, [6] TBPWGA{i}, [n] P{n}PWGA{i} (n=0..3)
{0xFFFFB181+2i} ICPWGA{i}H (i=48..63)
  [7] CTPWGA{i} ro, [4] RFPWGA{i}
{0xFFFFB200+2i} ICTAUB1I{i} 16-bit (i=0..15)
{0xFFFFB200+2i} ICTAUB1I{i}L (i=0..15)
  [7] MKTAUB1I{i}, [6] TBTAUB1I{i}, [n] P{n}TAUB1I{i} (n=0..3)
{0xFFFFB201+2i} ICTAUB1I{i}H (i=0..15)
  [7] CTTAUB1I{i} ro, [4] RFTAUB1I{i}
0xFFFFB220 ICRCAN4ERR 16-bit
0xFFFFB220 ICRCAN4ERRL
  [7] MKRCAN4ERR, [6] TBRCAN4ERR, [n] P{n}RCAN4ERR (n=0..3)
0xFFFFB221 ICRCAN4ERRH
  [7] CTRCAN4ERR ro, [4] RFRCAN4ERR
0xFFFFB222 ICRCAN4REC 16-bit
0xFFFFB222 ICRCAN4RECL
  [7] MKRCAN4REC, [6] TBRCAN4REC, [n] P{n}RCAN4REC (n=0..3)
0xFFFFB223 ICRCAN4RECH
  [7] CTRCAN4REC ro, [4] RFRCAN4REC
0xFFFFB224 ICRCAN4TRX 16-bit
0xFFFFB224 ICRCAN4TRXL
  [7] MKRCAN4TRX, [6] TBRCAN4TRX, [n] P{n}RCAN4TRX (n=0..3)
0xFFFFB225 ICRCAN4TRXH
  [7] CTRCAN4TRX ro, [4] RFRCAN4TRX
0xFFFFB226 ICRLIN26 16-bit
0xFFFFB226 ICRLIN26L
  [7] MKRLIN26, [6] TBRLIN26, [n] P{n}RLIN26 (n=0..3)
0xFFFFB227 ICRLIN26H
  [7] CTRLIN26 ro, [4] RFRLIN26
0xFFFFB228 ICRLIN27 16-bit
0xFFFFB228 ICRLIN27L
  [7] MKRLIN27, [6] TBRLIN27, [n] P{n}RLIN27 (n=0..3)
0xFFFFB229 ICRLIN27H
  [7] CTRLIN27 ro, [4] RFRLIN27
{0xFFFFB1AA+2i} ICPWGA{i} 16-bit (i=64..71)
{0xFFFFB1AA+2i} ICPWGA{i}L (i=64..71)
  [7] MKPWGA{i}, [6] TBPWGA{i}, [n] P{n}PWGA{i} (n=0..3)
{0xFFFFB1AB+2i} ICPWGA{i}H (i=64..71)
  [7] CTPWGA{i} ro, [4] RFPWGA{i}
0xFFFFB23A ICRLIN28 16-bit
0xFFFFB23A ICRLIN28L
  [7] MKRLIN28, [6] TBRLIN28, [n] P{n}RLIN28 (n=0..3)
0xFFFFB23B ICRLIN28H
  [7] CTRLIN28 ro, [4] RFRLIN28
0xFFFFB23C ICRLIN29 16-bit
0xFFFFB23C ICRLIN29L
  [7] MKRLIN29, [6] TBRLIN29, [n] P{n}RLIN29 (n=0..3)
0xFFFFB23D ICRLIN29H
  [7] CTRLIN29 ro, [4] RFRLIN29
0xFFFFB23E ICRCAN5ERR 16-bit
0xFFFFB23E ICRCAN5ERRL
  [7] MKRCAN5ERR, [6] TBRCAN5ERR, [n] P{n}RCAN5ERR (n=0..3)
0xFFFFB23F ICRCAN5ERRH
  [7] CTRCAN5ERR ro, [4] RFRCAN5ERR
0xFFFFB240 ICRCAN5REC 16-bit
0xFFFFB240 ICRCAN5RECL
  [7] MKRCAN5REC, [6] TBRCAN5REC, [n] P{n}RCAN5REC (n=0..3)
0xFFFFB241 ICRCAN5RECH
  [7] CTRCAN5REC ro, [4] RFRCAN5REC
0xFFFFB242 ICRCAN5TRX 16-bit
0xFFFFB242 ICRCAN5TRXL
  [7] MKRCAN5TRX, [6] TBRCAN5TRX, [n] P{n}RCAN5TRX (n=0..3)
0xFFFFB243 ICRCAN5TRXH
  [7] CTRCAN5TRX ro, [4] RFRCAN5TRX
{0xFFFFB234+2i} ICDMA{i} 16-bit (i=16..31)
{0xFFFFB234+2i} ICDMA{i}L (i=16..31)
  [7] MKDMA{i}, [6] TBDMA{i}, [n] P{n}DMA{i} (n=0..3)
{0xFFFFB235+2i} ICDMA{i}H (i=16..31)
  [7] CTDMA{i} ro, [4] RFDMA{i}
0xFFFFB274 ICOSTM5 16-bit
0xFFFFB274 ICOSTM5L
  [7] MKOSTM5, [6] TBOSTM5, [n] P{n}OSTM5 (n=0..3)
0xFFFFB275 ICOSTM5H
  [7] CTOSTM5 ro, [4] RFOSTM5
0xFFFFB276 ICETNB0DATA 16-bit
0xFFFFB276 ICETNB0DATAL
  [7] MKETNB0DATA, [6] TBETNB0DATA, [n] P{n}ETNB0DATA (n=0..3)
0xFFFFB277 ICETNB0DATAH
  [7] CTETNB0DATA ro, [4] RFETNB0DATA
0xFFFFB278 ICETNB0ERR 16-bit
0xFFFFB278 ICETNB0ERRL
  [7] MKETNB0ERR, [6] TBETNB0ERR, [n] P{n}ETNB0ERR (n=0..3)
0xFFFFB279 ICETNB0ERRH
  [7] CTETNB0ERR ro, [4] RFETNB0ERR
0xFFFFB27A ICETNB0MNG 16-bit
0xFFFFB27A ICETNB0MNGL
  [7] MKETNB0MNG, [6] TBETNB0MNG, [n] P{n}ETNB0MNG (n=0..3)
0xFFFFB27B ICETNB0MNGH
  [7] CTETNB0MNG ro, [4] RFETNB0MNG
0xFFFFB27C ICETNB0MAC 16-bit
0xFFFFB27C ICETNB0MACL
  [7] MKETNB0MAC, [6] TBETNB0MAC, [n] P{n}ETNB0MAC (n=0..3)
0xFFFFB27D ICETNB0MACH
  [7] CTETNB0MAC ro, [4] RFETNB0MAC
0xFFFFB27E ICRCANGERR1 16-bit
0xFFFFB27E ICRCANGERR1L
  [7] MKRCANGERR1, [6] TBRCANGERR1, [n] P{n}RCANGERR1 (n=0..3)
0xFFFFB27F ICRCANGERR1H
  [7] CTRCANGERR1 ro, [4] RFRCANGERR1
0xFFFFB280 ICRCANGRECC1 16-bit
0xFFFFB280 ICRCANGRECC1L
  [7] MKRCANGRECC1, [6] TBRCANGRECC1, [n] P{n}RCANGRECC1 (n=0..3)
0xFFFFB281 ICRCANGRECC1H
  [7] CTRCANGRECC1 ro, [4] RFRCANGRECC1
0xFFFFB282 ICRCAN6ERR 16-bit
0xFFFFB282 ICRCAN6ERRL
  [7] MKRCAN6ERR, [6] TBRCAN6ERR, [n] P{n}RCAN6ERR (n=0..3)
0xFFFFB283 ICRCAN6ERRH
  [7] CTRCAN6ERR ro, [4] RFRCAN6ERR
0xFFFFB284 ICRCAN6REC 16-bit
0xFFFFB284 ICRCAN6RECL
  [7] MKRCAN6REC, [6] TBRCAN6REC, [n] P{n}RCAN6REC (n=0..3)
0xFFFFB285 ICRCAN6RECH
  [7] CTRCAN6REC ro, [4] RFRCAN6REC
0xFFFFB286 ICRCAN6TRX 16-bit
0xFFFFB286 ICRCAN6TRXL
  [7] MKRCAN6TRX, [6] TBRCAN6TRX, [n] P{n}RCAN6TRX (n=0..3)
0xFFFFB287 ICRCAN6TRXH
  [7] CTRCAN6TRX ro, [4] RFRCAN6TRX
0xFFFFB28C ICCSIG2IC 16-bit
0xFFFFB28C ICCSIG2ICL
  [7] MKCSIG2IC, [6] TBCSIG2IC, [n] P{n}CSIG2IC (n=0..3)
0xFFFFB28D ICCSIG2ICH
  [7] CTCSIG2IC ro, [4] RFCSIG2IC
0xFFFFB28E ICCSIG2IR 16-bit
0xFFFFB28E ICCSIG2IRL
  [7] MKCSIG2IR, [6] TBCSIG2IR, [n] P{n}CSIG2IR (n=0..3)
0xFFFFB28F ICCSIG2IRH
  [7] CTCSIG2IR ro, [4] RFCSIG2IR
0xFFFFB290 ICCSIG2IRE 16-bit
0xFFFFB290 ICCSIG2IREL
  [7] MKCSIG2IRE, [6] TBCSIG2IRE, [n] P{n}CSIG2IRE (n=0..3)
0xFFFFB291 ICCSIG2IREH
  [7] CTCSIG2IRE ro, [4] RFCSIG2IRE
0xFFFFB292 ICCSIG3IC 16-bit
0xFFFFB292 ICCSIG3ICL
  [7] MKCSIG3IC, [6] TBCSIG3IC, [n] P{n}CSIG3IC (n=0..3)
0xFFFFB293 ICCSIG3ICH
  [7] CTCSIG3IC ro, [4] RFCSIG3IC
0xFFFFB294 ICCSIG3IR 16-bit
0xFFFFB294 ICCSIG3IRL
  [7] MKCSIG3IR, [6] TBCSIG3IR, [n] P{n}CSIG3IR (n=0..3)
0xFFFFB295 ICCSIG3IRH
  [7] CTCSIG3IR ro, [4] RFCSIG3IR
0xFFFFB296 ICCSIG3IRE 16-bit
0xFFFFB296 ICCSIG3IREL
  [7] MKCSIG3IRE, [6] TBCSIG3IRE, [n] P{n}CSIG3IRE (n=0..3)
0xFFFFB297 ICCSIG3IREH
  [7] CTCSIG3IRE ro, [4] RFCSIG3IRE
{0xFFFFB400+4i} IMR{i} 32-bit (i=1..10)
{0xFFFFB400+4i} IMR{i}L 16-bit (i=1..10)
0xFFFFB404 IMR1LL
  [n-32] IMR1EIMK{n} (n=32..39)
0xFFFFB405 IMR1LH
  [n-40] IMR1EIMK{n} (n=40..47)
{0xFFFFB402+4i} IMR{i}H 16-bit (i=1..9)
0xFFFFB406 IMR1HL
  [n-48] IMR1EIMK{n} (n=48..55)
0xFFFFB407 IMR1HH
  [n-56] IMR1EIMK{n} (n=56..63)
0xFFFFB408 IMR2LL
  [n-64] IMR2EIMK{n} (n=64..71)
0xFFFFB409 IMR2LH
  [n-72] IMR2EIMK{n} (n=72..79)
0xFFFFB40A IMR2HL
  [n-80] IMR2EIMK{n} (n=80..87)
0xFFFFB40B IMR2HH
  [n-88] IMR2EIMK{n} (n=88..95)
0xFFFFB40C IMR3LL
  [n-96] IMR3EIMK{n} (n=96..103)
0xFFFFB40D IMR3LH
  [7] IMR3EIMK111, [6] IMR3EIMK110
0xFFFFB40E IMR3HL
  [n-112] IMR3EIMK{n} (n=112..119)
0xFFFFB40F IMR3HH
  [n-120] IMR3EIMK{n} (n=120..127)
0xFFFFB410 IMR4LL
  [n-128] IMR4EIMK{n} (n=128..135)
0xFFFFB411 IMR4LH
  [7] IMR4EIMK143, [6] IMR4EIMK142
0xFFFFB412 IMR4HL
  [n-144] IMR4EIMK{n} (n=144..151)
0xFFFFB413 IMR4HH
  [n-152] IMR4EIMK{n} (n=152..159)
0xFFFFB414 IMR5LL
  [n-160] IMR5EIMK{n} (n=160..167)
0xFFFFB415 IMR5LH
  [7] IMR5EIMK175, [6] IMR5EIMK174, [5] IMR5EIMK173, [n-168] IMR5EIMK{n} (n=168..171)
0xFFFFB416 IMR5HL
  [n-176] IMR5EIMK{n} (n=176..183)
0xFFFFB417 IMR5HH
  [n-184] IMR5EIMK{n} (n=184..191)
0xFFFFB418 IMR6LL
  [n-192] IMR6EIMK{n} (n=192..199)
0xFFFFB419 IMR6LH
  [n-200] IMR6EIMK{n} (n=200..207)
0xFFFFB41A IMR6HL
  [n-208] IMR6EIMK{n} (n=208..215)
0xFFFFB41B IMR6HH
  [n-216] IMR6EIMK{n} (n=217..223)
0xFFFFB41C IMR7LL
  [n-224] IMR7EIMK{n} (n=224..231)
0xFFFFB41D IMR7LH
  [n-232] IMR7EIMK{n} (n=232..239)
0xFFFFB41E IMR7HL
  [n-240] IMR7EIMK{n} (n=240..247)
0xFFFFB41F IMR7HH
  [n-248] IMR7EIMK{n} (n=248..255)
0xFFFFB420 IMR8LL
  [n-256] IMR8EIMK{n} (n=256..263)
0xFFFFB421 IMR8LH
  [n-264] IMR8EIMK{n} (n=264..271)
0xFFFFB422 IMR8HL
  [n-272] IMR8EIMK{n} (n=272..279)
0xFFFFB423 IMR8HH
  [n-280] IMR8EIMK{n} (n=280..287)
0xFFFFB424 IMR9LL
  [1] IMR9EIMK289, [0] IMR9EIMK288
0xFFFFB425 IMR9LH
  [n-296] IMR9EIMK{n} (n=298..303)
0xFFFFB426 IMR9HL
  [n-304] IMR9EIMK{n} (n=304..311)
0xFFFFB427 IMR9HH
  [n-312] IMR9EIMK{n} (n=312..319)
0xFFFFB428 IMR10LL
  [7] IMR10EIMK327, [6] IMR10EIMK326, [n-320] IMR10EIMK{n} (n=320..323)
0xFFFFB429 IMR10LH
  [n-328] IMR10EIMK{n} (n=328..331)
0xFFFFB880 IBDCSIH0IJC 32-bit
0xFFFFB880 IBDADCA0I2_2 32-bit
0xFFFFB884 IBDRLIN30 32-bit
{0xFFFFB888+4i} IBDRLIN30UR{i} 32-bit (i=0..2)
{0xFFFFB894+4i} IBDP{i} 32-bit (i=0..2)
{0xFFFFB8A0+4i} IBDWDTA{i} 32-bit (i=0..2)
{0xFFFFB8A0+4i} IBDP{i} 32-bit (i=3..5)
0xFFFFB8B8 IBDP10 32-bit
0xFFFFB8BC IBDP11 32-bit
0xFFFFB8C0 IBDTAUD0I1 32-bit
0xFFFFB8C4 IBDTAUD0I3 32-bit
0xFFFFB8C8 IBDTAUD0I5 32-bit
0xFFFFB8CC IBDTAUD0I7 32-bit
0xFFFFB8D0 IBDTAUD0I9 32-bit
0xFFFFB8D4 IBDTAUD0I11 32-bit
0xFFFFB8D8 IBDTAUD0I13 32-bit
0xFFFFB8DC IBDTAUD0I15 32-bit
0xFFFFB8E0 IBDADCA0ERR 32-bit
0xFFFFB8E4 IBDCSIG0IRE 32-bit
0xFFFFB8E8 IBDRLIN20 32-bit
0xFFFFB8EC IBDRLIN21 32-bit
{0xFFFFB8F0+4i} IBDDMA{i} 32-bit (i=0..15)
0xFFFFB930 IBDRIIC0TI 32-bit
0xFFFFB934 IBDRIIC0TEI 32-bit
0xFFFFB938 IBDRIIC0RI 32-bit
0xFFFFB93C IBDRIIC0EE 32-bit
{0xFFFFB940+4i} IBDTAUJ0I{i} 32-bit (i=0..3)
0xFFFFB950 IBDOSTM0 32-bit
0xFFFFB954 IBDENCA0IOV 32-bit
{0xFFFFB944+4i} IBDPWGA{i} 32-bit (i=4..7)
0xFFFFB958 IBDENCA0IUD 32-bit
0xFFFFB95C IBDENCA0I0 32-bit
0xFFFFB960 IBDENCA0I1 32-bit
0xFFFFB964 IBDENCA0IEC 32-bit
0xFFFFB968 IBDKR0 32-bit
0xFFFFB96C IBDQFULL 32-bit
{0xFFFFB970+4i} IBDPWGA{i} 32-bit (i=0..3)
{0xFFFFB960+4i} IBDPWGA{i} 32-bit (i=8..15)
0xFFFFB9B8 IBDFLERR 32-bit
0xFFFFB9BC IBDFLENDNM 32-bit
0xFFFFB9C0 IBDCWEND 32-bit
0xFFFFB9C4 IBDRCAN1ERR 32-bit
0xFFFFB9C8 IBDRCAN1REC 32-bit
0xFFFFB9CC IBDRCAN1TRX 32-bit
0xFFFFB9D0 IBDCSIH1IC 32-bit
0xFFFFB9D0 IBDTAPA0IPEK0_2 32-bit
0xFFFFB9D4 IBDCSIH1IR 32-bit
0xFFFFB9D4 IBDTAPA0IVLY0_2 32-bit
0xFFFFB9D8 IBDCSIH1IRE 32-bit
0xFFFFB9D8 IBDCSIG0IC_2 32-bit
0xFFFFB9DC IBDCSIH1IJC 32-bit
0xFFFFB9DC IBDCSIG0IR_2 32-bit
0xFFFFB9E0 IBDRLIN31 32-bit
{0xFFFFB9E4+4i} IBDRLIN31UR{i} 32-bit (i=0..2)
{0xFFFFB9A0+4i} IBDPWGA{i} 32-bit (i=20..23)
{0xFFFFB9E8+4i} IBDP{i} 32-bit (i=6..8)
0xFFFFBA0C IBDP12 32-bit
0xFFFFBA10 IBDCSIH2IC 32-bit
0xFFFFBA10 IBDTAUD0I0_2 32-bit
0xFFFFBA14 IBDCSIH2IR 32-bit
0xFFFFBA14 IBDTAUD0I4_2 32-bit
0xFFFFBA18 IBDCSIH2IRE 32-bit
0xFFFFBA18 IBDTAUD0I6_2 32-bit
0xFFFFBA1C IBDCSIH2IJC 32-bit
0xFFFFBA1C IBDTAUD0I8_2 32-bit
{0xFFFFBA38+4i} IBDTAUB0I{i} 32-bit (i=0..15)
{0xFFFFB9C4+8i} IBDPWGA{i} 32-bit (i=16..19)
0xFFFFBA64 IBDPWGA26 32-bit
0xFFFFBA6C IBDPWGA30 32-bit
0xFFFFBA74 IBDPWGA31 32-bit
0xFFFFBA78 IBDCSIH3IC 32-bit
0xFFFFBA78 IBDTAUD0I2_2 32-bit
0xFFFFBA7C IBDCSIH3IR 32-bit
0xFFFFBA7C IBDTAUD0I10_2 32-bit
0xFFFFBA80 IBDCSIH3IRE 32-bit
0xFFFFBA80 IBDTAUD0I12_2 32-bit
0xFFFFBA84 IBDCSIH3IJC 32-bit
0xFFFFBA84 IBDTAUD0I14_2 32-bit
0xFFFFBA88 IBDRLIN22 32-bit
0xFFFFBA8C IBDRLIN23 32-bit
0xFFFFBA90 IBDRLIN32 32-bit
{0xFFFFBA94+4i} IBDRLIN32UR{i} 32-bit (i=0..2)
{0xFFFFBAA0+4i} IBDTAUJ1I{i} 32-bit (i=0..3)
0xFFFFBAB4 IBDFLXA0FDA 32-bit
0xFFFFBAB8 IBDFLXA0FW 32-bit
0xFFFFBABC IBDFLXA0IQE 32-bit
0xFFFFBAC0 IBDFLXA0IQF 32-bit
0xFFFFBAC4 IBDFLXA0OT 32-bit
0xFFFFBAC8 IBDFLXA0OW 32-bit
0xFFFFBACC IBDFLXA0LINE0 32-bit
0xFFFFBAD0 IBDFLXA0LINE1 32-bit
{0xFFFFBAD4+4i} IBDFLXA0TIM{i} 32-bit (i=0..2)
0xFFFFBAE0 IBDPWGA24 32-bit
0xFFFFBAE4 IBDPWGA25 32-bit
{0xFFFFBA7C+4i} IBDPWGA{i} 32-bit (i=27..29)
{0xFFFFBA74+4i} IBDPWGA{i} 32-bit (i=32..47)
0xFFFFBB34 IBDP9 32-bit
{0xFFFFBB04+4i} IBDP{i} 32-bit (i=13..15)
0xFFFFBB44 IBDRTCA01S 32-bit
0xFFFFBB48 IBDRTCA0AL 32-bit
0xFFFFBB4C IBDRTCA0R 32-bit
0xFFFFBB50 IBDADCA1ERR 32-bit
{0xFFFFBB54+4i} IBDADCA1I{i} 32-bit (i=0..2)
0xFFFFBB64 IBDRCAN2ERR 32-bit
0xFFFFBB68 IBDRCAN2REC 32-bit
0xFFFFBB6C IBDRCAN2TRX 32-bit
0xFFFFBB70 IBDRCAN3ERR 32-bit
0xFFFFBB74 IBDRCAN3REC 32-bit
0xFFFFBB78 IBDRCAN3TRX 32-bit
0xFFFFBB7C IBDCSIG1IC 32-bit
0xFFFFBB80 IBDCSIG1IR 32-bit
0xFFFFBB84 IBDCSIG1IRE 32-bit
0xFFFFBB88 IBDRLIN24 32-bit
0xFFFFBB8C IBDRLIN25 32-bit
{0xFFFFB980+0x10*i} IBDRLIN{i} 32-bit (i=33..35)
{0xFFFFBB94+4i} IBDRLIN33UR{i} 32-bit (i=0..2)
{0xFFFFBBA4+4i} IBDRLIN34UR{i} 32-bit (i=0..2)
{0xFFFFBBB4+4i} IBDRLIN35UR{i} 32-bit (i=0..2)
{0xFFFFBB00+4i} IBDPWGA{i} 32-bit (i=48..63)
{0xFFFFBC00+4i} IBDTAUB1I{i} 32-bit (i=0..15)
0xFFFFBC40 IBDRCAN4ERR 32-bit
0xFFFFBC44 IBDRCAN4REC 32-bit
0xFFFFBC48 IBDRCAN4TRX 32-bit
0xFFFFBC4C IBDRLIN26 32-bit
0xFFFFBC50 IBDRLIN27 32-bit
{0xFFFFBB54+4i} IBDPWGA{i} 32-bit (i=64..71)
0xFFFFBC74 IBDRLIN28 32-bit
0xFFFFBC78 IBDRLIN29 32-bit
0xFFFFBC7C IBDRCAN5ERR 32-bit
0xFFFFBC80 IBDRCAN5REC 32-bit
0xFFFFBC84 IBDRCAN5TRX 32-bit
{0xFFFFBC68+4i} IBDDMA{i} 32-bit (i=16..31)
0xFFFFBCE8 IBDOSTM5 32-bit
0xFFFFBCEC IBDETNB0DATA 32-bit
0xFFFFBCF0 IBDETNB0ERR 32-bit
0xFFFFBCF4 IBDETNB0MNG 32-bit
0xFFFFBCF8 IBDETNB0MAC 32-bit
0xFFFFBCFC IBDRCANGERR1 32-bit
0xFFFFBD00 IBDRCANGRECC1 32-bit
0xFFFFBD04 IBDRCAN6ERR 32-bit
0xFFFFBD08 IBDRCAN6REC 32-bit
0xFFFFBD0C IBDRCAN6TRX 32-bit
0xFFFFBD18 IBDCSIG2IC 32-bit
0xFFFFBD1C IBDCSIG2IR 32-bit
0xFFFFBD20 IBDCSIG2IRE 32-bit
0xFFFFBD24 IBDCSIG3IC 32-bit
0xFFFFBD28 IBDCSIG3IR 32-bit
0xFFFFBD2C IBDCSIG3IRE 32-bit

## Notices in the file
Copyright(C) 2014 Renesas
